VERSION 5.4 ;
NAMESCASESENSITIVE ON ;
BUSBITCHARS "[]" ;
DIVIDERCHAR "/" ;
UNITS
  DATABASE MICRONS 2000 ;
END UNITS
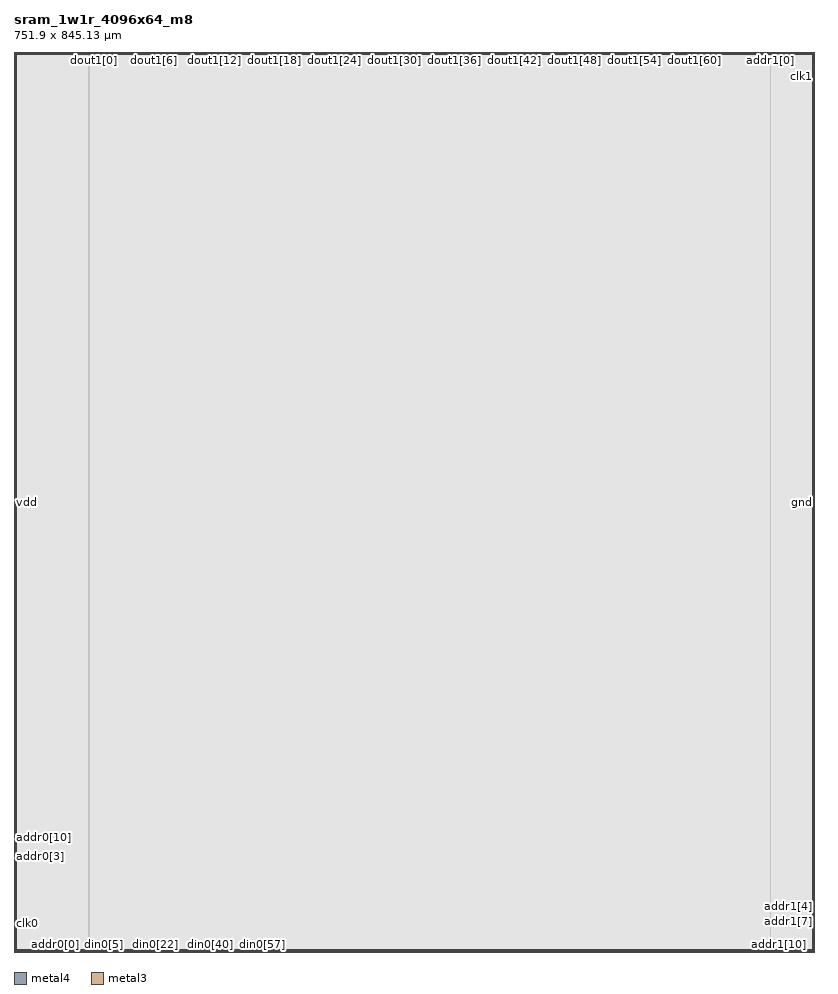
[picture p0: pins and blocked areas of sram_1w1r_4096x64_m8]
MACRO sram_1w1r_4096x64_m8
   CLASS BLOCK ;
   SIZE 751.9 BY 845.13 ;
   SYMMETRY X Y R90 ;
   PIN din0[0]
      DIRECTION INPUT ;
      PORT
         LAYER metal4 ;
         RECT  70.13 0.0 70.27 0.14 ;
      END
   END din0[0]
   PIN din0[1]
      DIRECTION INPUT ;
      PORT
         LAYER metal4 ;
         RECT  72.99 0.0 73.13 0.14 ;
      END
   END din0[1]
   PIN din0[2]
      DIRECTION INPUT ;
      PORT
         LAYER metal4 ;
         RECT  75.85 0.0 75.99 0.14 ;
      END
   END din0[2]
   PIN din0[3]
      DIRECTION INPUT ;
      PORT
         LAYER metal4 ;
         RECT  78.71 0.0 78.85 0.14 ;
      END
   END din0[3]
   PIN din0[4]
      DIRECTION INPUT ;
      PORT
         LAYER metal4 ;
         RECT  81.57 0.0 81.71 0.14 ;
      END
   END din0[4]
   PIN din0[5]
      DIRECTION INPUT ;
      PORT
         LAYER metal4 ;
         RECT  84.43 0.0 84.57 0.14 ;
      END
   END din0[5]
   PIN din0[6]
      DIRECTION INPUT ;
      PORT
         LAYER metal4 ;
         RECT  87.29 0.0 87.43 0.14 ;
      END
   END din0[6]
   PIN din0[7]
      DIRECTION INPUT ;
      PORT
         LAYER metal4 ;
         RECT  90.15 0.0 90.29 0.14 ;
      END
   END din0[7]
   PIN din0[8]
      DIRECTION INPUT ;
      PORT
         LAYER metal4 ;
         RECT  93.01 0.0 93.15 0.14 ;
      END
   END din0[8]
   PIN din0[9]
      DIRECTION INPUT ;
      PORT
         LAYER metal4 ;
         RECT  95.87 0.0 96.01 0.14 ;
      END
   END din0[9]
   PIN din0[10]
      DIRECTION INPUT ;
      PORT
         LAYER metal4 ;
         RECT  98.73 0.0 98.87 0.14 ;
      END
   END din0[10]
   PIN din0[11]
      DIRECTION INPUT ;
      PORT
         LAYER metal4 ;
         RECT  101.59 0.0 101.73 0.14 ;
      END
   END din0[11]
   PIN din0[12]
      DIRECTION INPUT ;
      PORT
         LAYER metal4 ;
         RECT  104.45 0.0 104.59 0.14 ;
      END
   END din0[12]
   PIN din0[13]
      DIRECTION INPUT ;
      PORT
         LAYER metal4 ;
         RECT  107.31 0.0 107.45 0.14 ;
      END
   END din0[13]
   PIN din0[14]
      DIRECTION INPUT ;
      PORT
         LAYER metal4 ;
         RECT  110.17 0.0 110.31 0.14 ;
      END
   END din0[14]
   PIN din0[15]
      DIRECTION INPUT ;
      PORT
         LAYER metal4 ;
         RECT  113.03 0.0 113.17 0.14 ;
      END
   END din0[15]
   PIN din0[16]
      DIRECTION INPUT ;
      PORT
         LAYER metal4 ;
         RECT  115.89 0.0 116.03 0.14 ;
      END
   END din0[16]
   PIN din0[17]
      DIRECTION INPUT ;
      PORT
         LAYER metal4 ;
         RECT  118.75 0.0 118.89 0.14 ;
      END
   END din0[17]
   PIN din0[18]
      DIRECTION INPUT ;
      PORT
         LAYER metal4 ;
         RECT  121.61 0.0 121.75 0.14 ;
      END
   END din0[18]
   PIN din0[19]
      DIRECTION INPUT ;
      PORT
         LAYER metal4 ;
         RECT  124.47 0.0 124.61 0.14 ;
      END
   END din0[19]
   PIN din0[20]
      DIRECTION INPUT ;
      PORT
         LAYER metal4 ;
         RECT  127.33 0.0 127.47 0.14 ;
      END
   END din0[20]
   PIN din0[21]
      DIRECTION INPUT ;
      PORT
         LAYER metal4 ;
         RECT  130.19 0.0 130.33 0.14 ;
      END
   END din0[21]
   PIN din0[22]
      DIRECTION INPUT ;
      PORT
         LAYER metal4 ;
         RECT  133.05 0.0 133.19 0.14 ;
      END
   END din0[22]
   PIN din0[23]
      DIRECTION INPUT ;
      PORT
         LAYER metal4 ;
         RECT  135.91 0.0 136.05 0.14 ;
      END
   END din0[23]
   PIN din0[24]
      DIRECTION INPUT ;
      PORT
         LAYER metal4 ;
         RECT  138.77 0.0 138.91 0.14 ;
      END
   END din0[24]
   PIN din0[25]
      DIRECTION INPUT ;
      PORT
         LAYER metal4 ;
         RECT  141.63 0.0 141.77 0.14 ;
      END
   END din0[25]
   PIN din0[26]
      DIRECTION INPUT ;
      PORT
         LAYER metal4 ;
         RECT  144.49 0.0 144.63 0.14 ;
      END
   END din0[26]
   PIN din0[27]
      DIRECTION INPUT ;
      PORT
         LAYER metal4 ;
         RECT  147.35 0.0 147.49 0.14 ;
      END
   END din0[27]
   PIN din0[28]
      DIRECTION INPUT ;
      PORT
         LAYER metal4 ;
         RECT  150.21 0.0 150.35 0.14 ;
      END
   END din0[28]
   PIN din0[29]
      DIRECTION INPUT ;
      PORT
         LAYER metal4 ;
         RECT  153.07 0.0 153.21 0.14 ;
      END
   END din0[29]
   PIN din0[30]
      DIRECTION INPUT ;
      PORT
         LAYER metal4 ;
         RECT  155.93 0.0 156.07 0.14 ;
      END
   END din0[30]
   PIN din0[31]
      DIRECTION INPUT ;
      PORT
         LAYER metal4 ;
         RECT  158.79 0.0 158.93 0.14 ;
      END
   END din0[31]
   PIN din0[32]
      DIRECTION INPUT ;
      PORT
         LAYER metal4 ;
         RECT  161.65 0.0 161.79 0.14 ;
      END
   END din0[32]
   PIN din0[33]
      DIRECTION INPUT ;
      PORT
         LAYER metal4 ;
         RECT  164.51 0.0 164.65 0.14 ;
      END
   END din0[33]
   PIN din0[34]
      DIRECTION INPUT ;
      PORT
         LAYER metal4 ;
         RECT  167.37 0.0 167.51 0.14 ;
      END
   END din0[34]
   PIN din0[35]
      DIRECTION INPUT ;
      PORT
         LAYER metal4 ;
         RECT  170.23 0.0 170.37 0.14 ;
      END
   END din0[35]
   PIN din0[36]
      DIRECTION INPUT ;
      PORT
         LAYER metal4 ;
         RECT  173.09 0.0 173.23 0.14 ;
      END
   END din0[36]
   PIN din0[37]
      DIRECTION INPUT ;
      PORT
         LAYER metal4 ;
         RECT  175.95 0.0 176.09 0.14 ;
      END
   END din0[37]
   PIN din0[38]
      DIRECTION INPUT ;
      PORT
         LAYER metal4 ;
         RECT  178.81 0.0 178.95 0.14 ;
      END
   END din0[38]
   PIN din0[39]
      DIRECTION INPUT ;
      PORT
         LAYER metal4 ;
         RECT  181.67 0.0 181.81 0.14 ;
      END
   END din0[39]
   PIN din0[40]
      DIRECTION INPUT ;
      PORT
         LAYER metal4 ;
         RECT  184.53 0.0 184.67 0.14 ;
      END
   END din0[40]
   PIN din0[41]
      DIRECTION INPUT ;
      PORT
         LAYER metal4 ;
         RECT  187.39 0.0 187.53 0.14 ;
      END
   END din0[41]
   PIN din0[42]
      DIRECTION INPUT ;
      PORT
         LAYER metal4 ;
         RECT  190.25 0.0 190.39 0.14 ;
      END
   END din0[42]
   PIN din0[43]
      DIRECTION INPUT ;
      PORT
         LAYER metal4 ;
         RECT  193.11 0.0 193.25 0.14 ;
      END
   END din0[43]
   PIN din0[44]
      DIRECTION INPUT ;
      PORT
         LAYER metal4 ;
         RECT  195.97 0.0 196.11 0.14 ;
      END
   END din0[44]
   PIN din0[45]
      DIRECTION INPUT ;
      PORT
         LAYER metal4 ;
         RECT  198.83 0.0 198.97 0.14 ;
      END
   END din0[45]
   PIN din0[46]
      DIRECTION INPUT ;
      PORT
         LAYER metal4 ;
         RECT  201.69 0.0 201.83 0.14 ;
      END
   END din0[46]
   PIN din0[47]
      DIRECTION INPUT ;
      PORT
         LAYER metal4 ;
         RECT  204.55 0.0 204.69 0.14 ;
      END
   END din0[47]
   PIN din0[48]
      DIRECTION INPUT ;
      PORT
         LAYER metal4 ;
         RECT  207.41 0.0 207.55 0.14 ;
      END
   END din0[48]
   PIN din0[49]
      DIRECTION INPUT ;
      PORT
         LAYER metal4 ;
         RECT  210.27 0.0 210.41 0.14 ;
      END
   END din0[49]
   PIN din0[50]
      DIRECTION INPUT ;
      PORT
         LAYER metal4 ;
         RECT  213.13 0.0 213.27 0.14 ;
      END
   END din0[50]
   PIN din0[51]
      DIRECTION INPUT ;
      PORT
         LAYER metal4 ;
         RECT  215.99 0.0 216.13 0.14 ;
      END
   END din0[51]
   PIN din0[52]
      DIRECTION INPUT ;
      PORT
         LAYER metal4 ;
         RECT  218.85 0.0 218.99 0.14 ;
      END
   END din0[52]
   PIN din0[53]
      DIRECTION INPUT ;
      PORT
         LAYER metal4 ;
         RECT  221.71 0.0 221.85 0.14 ;
      END
   END din0[53]
   PIN din0[54]
      DIRECTION INPUT ;
      PORT
         LAYER metal4 ;
         RECT  224.57 0.0 224.71 0.14 ;
      END
   END din0[54]
   PIN din0[55]
      DIRECTION INPUT ;
      PORT
         LAYER metal4 ;
         RECT  227.43 0.0 227.57 0.14 ;
      END
   END din0[55]
   PIN din0[56]
      DIRECTION INPUT ;
      PORT
         LAYER metal4 ;
         RECT  230.29 0.0 230.43 0.14 ;
      END
   END din0[56]
   PIN din0[57]
      DIRECTION INPUT ;
      PORT
         LAYER metal4 ;
         RECT  233.15 0.0 233.29 0.14 ;
      END
   END din0[57]
   PIN din0[58]
      DIRECTION INPUT ;
      PORT
         LAYER metal4 ;
         RECT  236.01 0.0 236.15 0.14 ;
      END
   END din0[58]
   PIN din0[59]
      DIRECTION INPUT ;
      PORT
         LAYER metal4 ;
         RECT  238.87 0.0 239.01 0.14 ;
      END
   END din0[59]
   PIN din0[60]
      DIRECTION INPUT ;
      PORT
         LAYER metal4 ;
         RECT  241.73 0.0 241.87 0.14 ;
      END
   END din0[60]
   PIN din0[61]
      DIRECTION INPUT ;
      PORT
         LAYER metal4 ;
         RECT  244.59 0.0 244.73 0.14 ;
      END
   END din0[61]
   PIN din0[62]
      DIRECTION INPUT ;
      PORT
         LAYER metal4 ;
         RECT  247.45 0.0 247.59 0.14 ;
      END
   END din0[62]
   PIN din0[63]
      DIRECTION INPUT ;
      PORT
         LAYER metal4 ;
         RECT  250.31 0.0 250.45 0.14 ;
      END
   END din0[63]
   PIN addr0[0]
      DIRECTION INPUT ;
      PORT
         LAYER metal4 ;
         RECT  38.67 0.0 38.81 0.14 ;
      END
   END addr0[0]
   PIN addr0[1]
      DIRECTION INPUT ;
      PORT
         LAYER metal4 ;
         RECT  41.53 0.0 41.67 0.14 ;
      END
   END addr0[1]
   PIN addr0[2]
      DIRECTION INPUT ;
      PORT
         LAYER metal4 ;
         RECT  44.39 0.0 44.53 0.14 ;
      END
   END addr0[2]
   PIN addr0[3]
      DIRECTION INPUT ;
      PORT
         LAYER metal3 ;
         RECT  0.0 89.64 0.14 89.78 ;
      END
   END addr0[3]
   PIN addr0[4]
      DIRECTION INPUT ;
      PORT
         LAYER metal3 ;
         RECT  0.0 92.37 0.14 92.51 ;
      END
   END addr0[4]
   PIN addr0[5]
      DIRECTION INPUT ;
      PORT
         LAYER metal3 ;
         RECT  0.0 94.58 0.14 94.72 ;
      END
   END addr0[5]
   PIN addr0[6]
      DIRECTION INPUT ;
      PORT
         LAYER metal3 ;
         RECT  0.0 97.31 0.14 97.45 ;
      END
   END addr0[6]
   PIN addr0[7]
      DIRECTION INPUT ;
      PORT
         LAYER metal3 ;
         RECT  0.0 99.52 0.14 99.66 ;
      END
   END addr0[7]
   PIN addr0[8]
      DIRECTION INPUT ;
      PORT
         LAYER metal3 ;
         RECT  0.0 102.25 0.14 102.39 ;
      END
   END addr0[8]
   PIN addr0[9]
      DIRECTION INPUT ;
      PORT
         LAYER metal3 ;
         RECT  0.0 104.46 0.14 104.6 ;
      END
   END addr0[9]
   PIN addr0[10]
      DIRECTION INPUT ;
      PORT
         LAYER metal3 ;
         RECT  0.0 107.19 0.14 107.33 ;
      END
   END addr0[10]
   PIN addr0[11]
      DIRECTION INPUT ;
      PORT
         LAYER metal3 ;
         RECT  0.0 109.4 0.14 109.54 ;
      END
   END addr0[11]
   PIN addr1[0]
      DIRECTION INPUT ;
      PORT
         LAYER metal4 ;
         RECT  710.23 844.99 710.37 845.13 ;
      END
   END addr1[0]
   PIN addr1[1]
      DIRECTION INPUT ;
      PORT
         LAYER metal4 ;
         RECT  707.37 844.99 707.51 845.13 ;
      END
   END addr1[1]
   PIN addr1[2]
      DIRECTION INPUT ;
      PORT
         LAYER metal4 ;
         RECT  704.51 844.99 704.65 845.13 ;
      END
   END addr1[2]
   PIN addr1[3]
      DIRECTION INPUT ;
      PORT
         LAYER metal3 ;
         RECT  751.76 45.57 751.9 45.71 ;
      END
   END addr1[3]
   PIN addr1[4]
      DIRECTION INPUT ;
      PORT
         LAYER metal3 ;
         RECT  751.76 42.84 751.9 42.98 ;
      END
   END addr1[4]
   PIN addr1[5]
      DIRECTION INPUT ;
      PORT
         LAYER metal3 ;
         RECT  751.76 40.63 751.9 40.77 ;
      END
   END addr1[5]
   PIN addr1[6]
      DIRECTION INPUT ;
      PORT
         LAYER metal3 ;
         RECT  751.76 37.9 751.9 38.04 ;
      END
   END addr1[6]
   PIN addr1[7]
      DIRECTION INPUT ;
      PORT
         LAYER metal3 ;
         RECT  751.76 35.69 751.9 35.83 ;
      END
   END addr1[7]
   PIN addr1[8]
      DIRECTION INPUT ;
      PORT
         LAYER metal3 ;
         RECT  751.76 32.96 751.9 33.1 ;
      END
   END addr1[8]
   PIN addr1[9]
      DIRECTION INPUT ;
      PORT
         LAYER metal4 ;
         RECT  719.375 0.0 719.52 0.14 ;
      END
   END addr1[9]
   PIN addr1[10]
      DIRECTION INPUT ;
      PORT
         LAYER metal4 ;
         RECT  718.52 0.0 718.665 0.14 ;
      END
   END addr1[10]
   PIN addr1[11]
      DIRECTION INPUT ;
      PORT
         LAYER metal4 ;
         RECT  718.805 0.0 718.95 0.14 ;
      END
   END addr1[11]
   PIN csb0
      DIRECTION INPUT ;
      PORT
         LAYER metal3 ;
         RECT  0.0 26.8 0.14 26.94 ;
      END
   END csb0
   PIN csb1
      DIRECTION INPUT ;
      PORT
         LAYER metal3 ;
         RECT  751.76 829.52 751.9 829.66 ;
      END
   END csb1
   PIN clk0
      DIRECTION INPUT ;
      PORT
         LAYER metal3 ;
         RECT  0.0 27.035 0.14 27.175 ;
      END
   END clk0
   PIN clk1
      DIRECTION INPUT ;
      PORT
         LAYER metal3 ;
         RECT  751.76 829.285 751.9 829.425 ;
      END
   END clk1
   PIN wmask0[0]
      DIRECTION INPUT ;
      PORT
         LAYER metal4 ;
         RECT  47.25 0.0 47.39 0.14 ;
      END
   END wmask0[0]
   PIN wmask0[1]
      DIRECTION INPUT ;
      PORT
         LAYER metal4 ;
         RECT  50.11 0.0 50.25 0.14 ;
      END
   END wmask0[1]
   PIN wmask0[2]
      DIRECTION INPUT ;
      PORT
         LAYER metal4 ;
         RECT  52.97 0.0 53.11 0.14 ;
      END
   END wmask0[2]
   PIN wmask0[3]
      DIRECTION INPUT ;
      PORT
         LAYER metal4 ;
         RECT  55.83 0.0 55.97 0.14 ;
      END
   END wmask0[3]
   PIN wmask0[4]
      DIRECTION INPUT ;
      PORT
         LAYER metal4 ;
         RECT  58.69 0.0 58.83 0.14 ;
      END
   END wmask0[4]
   PIN wmask0[5]
      DIRECTION INPUT ;
      PORT
         LAYER metal4 ;
         RECT  61.55 0.0 61.69 0.14 ;
      END
   END wmask0[5]
   PIN wmask0[6]
      DIRECTION INPUT ;
      PORT
         LAYER metal4 ;
         RECT  64.41 0.0 64.55 0.14 ;
      END
   END wmask0[6]
   PIN wmask0[7]
      DIRECTION INPUT ;
      PORT
         LAYER metal4 ;
         RECT  67.27 0.0 67.41 0.14 ;
      END
   END wmask0[7]
   PIN dout1[0]
      DIRECTION OUTPUT ;
      PORT
         LAYER metal4 ;
         RECT  75.01 844.99 75.15 845.13 ;
      END
   END dout1[0]
   PIN dout1[1]
      DIRECTION OUTPUT ;
      PORT
         LAYER metal4 ;
         RECT  84.41 844.99 84.55 845.13 ;
      END
   END dout1[1]
   PIN dout1[2]
      DIRECTION OUTPUT ;
      PORT
         LAYER metal4 ;
         RECT  93.81 844.99 93.95 845.13 ;
      END
   END dout1[2]
   PIN dout1[3]
      DIRECTION OUTPUT ;
      PORT
         LAYER metal4 ;
         RECT  103.21 844.99 103.35 845.13 ;
      END
   END dout1[3]
   PIN dout1[4]
      DIRECTION OUTPUT ;
      PORT
         LAYER metal4 ;
         RECT  112.61 844.99 112.75 845.13 ;
      END
   END dout1[4]
   PIN dout1[5]
      DIRECTION OUTPUT ;
      PORT
         LAYER metal4 ;
         RECT  122.01 844.99 122.15 845.13 ;
      END
   END dout1[5]
   PIN dout1[6]
      DIRECTION OUTPUT ;
      PORT
         LAYER metal4 ;
         RECT  131.41 844.99 131.55 845.13 ;
      END
   END dout1[6]
   PIN dout1[7]
      DIRECTION OUTPUT ;
      PORT
         LAYER metal4 ;
         RECT  140.81 844.99 140.95 845.13 ;
      END
   END dout1[7]
   PIN dout1[8]
      DIRECTION OUTPUT ;
      PORT
         LAYER metal4 ;
         RECT  150.21 844.99 150.35 845.13 ;
      END
   END dout1[8]
   PIN dout1[9]
      DIRECTION OUTPUT ;
      PORT
         LAYER metal4 ;
         RECT  159.61 844.99 159.75 845.13 ;
      END
   END dout1[9]
   PIN dout1[10]
      DIRECTION OUTPUT ;
      PORT
         LAYER metal4 ;
         RECT  169.01 844.99 169.15 845.13 ;
      END
   END dout1[10]
   PIN dout1[11]
      DIRECTION OUTPUT ;
      PORT
         LAYER metal4 ;
         RECT  178.41 844.99 178.55 845.13 ;
      END
   END dout1[11]
   PIN dout1[12]
      DIRECTION OUTPUT ;
      PORT
         LAYER metal4 ;
         RECT  187.81 844.99 187.95 845.13 ;
      END
   END dout1[12]
   PIN dout1[13]
      DIRECTION OUTPUT ;
      PORT
         LAYER metal4 ;
         RECT  197.21 844.99 197.35 845.13 ;
      END
   END dout1[13]
   PIN dout1[14]
      DIRECTION OUTPUT ;
      PORT
         LAYER metal4 ;
         RECT  206.61 844.99 206.75 845.13 ;
      END
   END dout1[14]
   PIN dout1[15]
      DIRECTION OUTPUT ;
      PORT
         LAYER metal4 ;
         RECT  216.01 844.99 216.15 845.13 ;
      END
   END dout1[15]
   PIN dout1[16]
      DIRECTION OUTPUT ;
      PORT
         LAYER metal4 ;
         RECT  225.41 844.99 225.55 845.13 ;
      END
   END dout1[16]
   PIN dout1[17]
      DIRECTION OUTPUT ;
      PORT
         LAYER metal4 ;
         RECT  234.81 844.99 234.95 845.13 ;
      END
   END dout1[17]
   PIN dout1[18]
      DIRECTION OUTPUT ;
      PORT
         LAYER metal4 ;
         RECT  244.21 844.99 244.35 845.13 ;
      END
   END dout1[18]
   PIN dout1[19]
      DIRECTION OUTPUT ;
      PORT
         LAYER metal4 ;
         RECT  253.61 844.99 253.75 845.13 ;
      END
   END dout1[19]
   PIN dout1[20]
      DIRECTION OUTPUT ;
      PORT
         LAYER metal4 ;
         RECT  263.01 844.99 263.15 845.13 ;
      END
   END dout1[20]
   PIN dout1[21]
      DIRECTION OUTPUT ;
      PORT
         LAYER metal4 ;
         RECT  272.41 844.99 272.55 845.13 ;
      END
   END dout1[21]
   PIN dout1[22]
      DIRECTION OUTPUT ;
      PORT
         LAYER metal4 ;
         RECT  281.81 844.99 281.95 845.13 ;
      END
   END dout1[22]
   PIN dout1[23]
      DIRECTION OUTPUT ;
      PORT
         LAYER metal4 ;
         RECT  291.21 844.99 291.35 845.13 ;
      END
   END dout1[23]
   PIN dout1[24]
      DIRECTION OUTPUT ;
      PORT
         LAYER metal4 ;
         RECT  300.61 844.99 300.75 845.13 ;
      END
   END dout1[24]
   PIN dout1[25]
      DIRECTION OUTPUT ;
      PORT
         LAYER metal4 ;
         RECT  310.01 844.99 310.15 845.13 ;
      END
   END dout1[25]
   PIN dout1[26]
      DIRECTION OUTPUT ;
      PORT
         LAYER metal4 ;
         RECT  319.41 844.99 319.55 845.13 ;
      END
   END dout1[26]
   PIN dout1[27]
      DIRECTION OUTPUT ;
      PORT
         LAYER metal4 ;
         RECT  328.81 844.99 328.95 845.13 ;
      END
   END dout1[27]
   PIN dout1[28]
      DIRECTION OUTPUT ;
      PORT
         LAYER metal4 ;
         RECT  338.21 844.99 338.35 845.13 ;
      END
   END dout1[28]
   PIN dout1[29]
      DIRECTION OUTPUT ;
      PORT
         LAYER metal4 ;
         RECT  347.61 844.99 347.75 845.13 ;
      END
   END dout1[29]
   PIN dout1[30]
      DIRECTION OUTPUT ;
      PORT
         LAYER metal4 ;
         RECT  357.01 844.99 357.15 845.13 ;
      END
   END dout1[30]
   PIN dout1[31]
      DIRECTION OUTPUT ;
      PORT
         LAYER metal4 ;
         RECT  366.41 844.99 366.55 845.13 ;
      END
   END dout1[31]
   PIN dout1[32]
      DIRECTION OUTPUT ;
      PORT
         LAYER metal4 ;
         RECT  375.81 844.99 375.95 845.13 ;
      END
   END dout1[32]
   PIN dout1[33]
      DIRECTION OUTPUT ;
      PORT
         LAYER metal4 ;
         RECT  385.21 844.99 385.35 845.13 ;
      END
   END dout1[33]
   PIN dout1[34]
      DIRECTION OUTPUT ;
      PORT
         LAYER metal4 ;
         RECT  394.61 844.99 394.75 845.13 ;
      END
   END dout1[34]
   PIN dout1[35]
      DIRECTION OUTPUT ;
      PORT
         LAYER metal4 ;
         RECT  404.01 844.99 404.15 845.13 ;
      END
   END dout1[35]
   PIN dout1[36]
      DIRECTION OUTPUT ;
      PORT
         LAYER metal4 ;
         RECT  413.41 844.99 413.55 845.13 ;
      END
   END dout1[36]
   PIN dout1[37]
      DIRECTION OUTPUT ;
      PORT
         LAYER metal4 ;
         RECT  422.81 844.99 422.95 845.13 ;
      END
   END dout1[37]
   PIN dout1[38]
      DIRECTION OUTPUT ;
      PORT
         LAYER metal4 ;
         RECT  432.21 844.99 432.35 845.13 ;
      END
   END dout1[38]
   PIN dout1[39]
      DIRECTION OUTPUT ;
      PORT
         LAYER metal4 ;
         RECT  441.61 844.99 441.75 845.13 ;
      END
   END dout1[39]
   PIN dout1[40]
      DIRECTION OUTPUT ;
      PORT
         LAYER metal4 ;
         RECT  451.01 844.99 451.15 845.13 ;
      END
   END dout1[40]
   PIN dout1[41]
      DIRECTION OUTPUT ;
      PORT
         LAYER metal4 ;
         RECT  460.41 844.99 460.55 845.13 ;
      END
   END dout1[41]
   PIN dout1[42]
      DIRECTION OUTPUT ;
      PORT
         LAYER metal4 ;
         RECT  469.81 844.99 469.95 845.13 ;
      END
   END dout1[42]
   PIN dout1[43]
      DIRECTION OUTPUT ;
      PORT
         LAYER metal4 ;
         RECT  479.21 844.99 479.35 845.13 ;
      END
   END dout1[43]
   PIN dout1[44]
      DIRECTION OUTPUT ;
      PORT
         LAYER metal4 ;
         RECT  488.61 844.99 488.75 845.13 ;
      END
   END dout1[44]
   PIN dout1[45]
      DIRECTION OUTPUT ;
      PORT
         LAYER metal4 ;
         RECT  498.01 844.99 498.15 845.13 ;
      END
   END dout1[45]
   PIN dout1[46]
      DIRECTION OUTPUT ;
      PORT
         LAYER metal4 ;
         RECT  507.41 844.99 507.55 845.13 ;
      END
   END dout1[46]
   PIN dout1[47]
      DIRECTION OUTPUT ;
      PORT
         LAYER metal4 ;
         RECT  516.81 844.99 516.95 845.13 ;
      END
   END dout1[47]
   PIN dout1[48]
      DIRECTION OUTPUT ;
      PORT
         LAYER metal4 ;
         RECT  526.21 844.99 526.35 845.13 ;
      END
   END dout1[48]
   PIN dout1[49]
      DIRECTION OUTPUT ;
      PORT
         LAYER metal4 ;
         RECT  535.61 844.99 535.75 845.13 ;
      END
   END dout1[49]
   PIN dout1[50]
      DIRECTION OUTPUT ;
      PORT
         LAYER metal4 ;
         RECT  545.01 844.99 545.15 845.13 ;
      END
   END dout1[50]
   PIN dout1[51]
      DIRECTION OUTPUT ;
      PORT
         LAYER metal4 ;
         RECT  554.41 844.99 554.55 845.13 ;
      END
   END dout1[51]
   PIN dout1[52]
      DIRECTION OUTPUT ;
      PORT
         LAYER metal4 ;
         RECT  563.81 844.99 563.95 845.13 ;
      END
   END dout1[52]
   PIN dout1[53]
      DIRECTION OUTPUT ;
      PORT
         LAYER metal4 ;
         RECT  573.21 844.99 573.35 845.13 ;
      END
   END dout1[53]
   PIN dout1[54]
      DIRECTION OUTPUT ;
      PORT
         LAYER metal4 ;
         RECT  582.61 844.99 582.75 845.13 ;
      END
   END dout1[54]
   PIN dout1[55]
      DIRECTION OUTPUT ;
      PORT
         LAYER metal4 ;
         RECT  592.01 844.99 592.15 845.13 ;
      END
   END dout1[55]
   PIN dout1[56]
      DIRECTION OUTPUT ;
      PORT
         LAYER metal4 ;
         RECT  601.41 844.99 601.55 845.13 ;
      END
   END dout1[56]
   PIN dout1[57]
      DIRECTION OUTPUT ;
      PORT
         LAYER metal4 ;
         RECT  610.81 844.99 610.95 845.13 ;
      END
   END dout1[57]
   PIN dout1[58]
      DIRECTION OUTPUT ;
      PORT
         LAYER metal4 ;
         RECT  620.21 844.99 620.35 845.13 ;
      END
   END dout1[58]
   PIN dout1[59]
      DIRECTION OUTPUT ;
      PORT
         LAYER metal4 ;
         RECT  629.61 844.99 629.75 845.13 ;
      END
   END dout1[59]
   PIN dout1[60]
      DIRECTION OUTPUT ;
      PORT
         LAYER metal4 ;
         RECT  639.01 844.99 639.15 845.13 ;
      END
   END dout1[60]
   PIN dout1[61]
      DIRECTION OUTPUT ;
      PORT
         LAYER metal4 ;
         RECT  648.41 844.99 648.55 845.13 ;
      END
   END dout1[61]
   PIN dout1[62]
      DIRECTION OUTPUT ;
      PORT
         LAYER metal4 ;
         RECT  657.81 844.99 657.95 845.13 ;
      END
   END dout1[62]
   PIN dout1[63]
      DIRECTION OUTPUT ;
      PORT
         LAYER metal4 ;
         RECT  667.21 844.99 667.35 845.13 ;
      END
   END dout1[63]
   PIN vdd
      DIRECTION INOUT ;
      USE POWER ; 
      SHAPE ABUTMENT ; 
      PORT
         LAYER metal4 ;
         RECT  0.0 0.0 0.7 845.13 ;
         LAYER metal4 ;
         RECT  751.2 0.0 751.9 845.13 ;
         LAYER metal3 ;
         RECT  0.0 0.0 751.9 0.7 ;
         LAYER metal3 ;
         RECT  0.0 844.43 751.9 845.13 ;
      END
   END vdd
   PIN gnd
      DIRECTION INOUT ;
      USE GROUND ; 
      SHAPE ABUTMENT ; 
      PORT
         LAYER metal4 ;
         RECT  1.4 1.4 2.1 843.73 ;
         LAYER metal3 ;
         RECT  1.4 1.4 750.5 2.1 ;
         LAYER metal4 ;
         RECT  749.8 1.4 750.5 843.73 ;
         LAYER metal3 ;
         RECT  1.4 843.03 750.5 843.73 ;
      END
   END gnd
   OBS
   LAYER  metal1 ;
      RECT  0.14 0.14 751.76 844.99 ;
   LAYER  metal2 ;
      RECT  0.14 0.14 751.76 844.99 ;
   LAYER  metal3 ;
      RECT  0.28 89.5 751.76 89.92 ;
      RECT  0.14 89.92 0.28 92.23 ;
      RECT  0.14 92.65 0.28 94.44 ;
      RECT  0.14 94.86 0.28 97.17 ;
      RECT  0.14 97.59 0.28 99.38 ;
      RECT  0.14 99.8 0.28 102.11 ;
      RECT  0.14 102.53 0.28 104.32 ;
      RECT  0.14 104.74 0.28 107.05 ;
      RECT  0.14 107.47 0.28 109.26 ;
      RECT  0.28 45.43 751.62 45.85 ;
      RECT  0.28 45.85 751.62 89.5 ;
      RECT  751.62 45.85 751.76 89.5 ;
      RECT  751.62 43.12 751.76 45.43 ;
      RECT  751.62 40.91 751.76 42.7 ;
      RECT  751.62 38.18 751.76 40.49 ;
      RECT  751.62 35.97 751.76 37.76 ;
      RECT  751.62 33.24 751.76 35.55 ;
      RECT  0.28 89.92 751.62 829.38 ;
      RECT  0.28 829.38 751.62 829.8 ;
      RECT  0.14 27.315 0.28 89.5 ;
      RECT  751.62 89.92 751.76 829.145 ;
      RECT  751.62 0.84 751.76 32.82 ;
      RECT  0.14 0.84 0.28 26.66 ;
      RECT  0.14 109.68 0.28 844.29 ;
      RECT  751.62 829.8 751.76 844.29 ;
      RECT  0.28 0.84 1.26 1.26 ;
      RECT  0.28 1.26 1.26 2.24 ;
      RECT  0.28 2.24 1.26 45.43 ;
      RECT  1.26 0.84 750.64 1.26 ;
      RECT  1.26 2.24 750.64 45.43 ;
      RECT  750.64 0.84 751.62 1.26 ;
      RECT  750.64 1.26 751.62 2.24 ;
      RECT  750.64 2.24 751.62 45.43 ;
      RECT  0.28 829.8 1.26 842.89 ;
      RECT  0.28 842.89 1.26 843.87 ;
      RECT  0.28 843.87 1.26 844.29 ;
      RECT  1.26 829.8 750.64 842.89 ;
      RECT  1.26 843.87 750.64 844.29 ;
      RECT  750.64 829.8 751.62 842.89 ;
      RECT  750.64 842.89 751.62 843.87 ;
      RECT  750.64 843.87 751.62 844.29 ;
   LAYER  metal4 ;
      RECT  69.85 0.42 70.55 844.99 ;
      RECT  70.55 0.14 72.71 0.42 ;
      RECT  73.41 0.14 75.57 0.42 ;
      RECT  76.27 0.14 78.43 0.42 ;
      RECT  79.13 0.14 81.29 0.42 ;
      RECT  81.99 0.14 84.15 0.42 ;
      RECT  84.85 0.14 87.01 0.42 ;
      RECT  87.71 0.14 89.87 0.42 ;
      RECT  90.57 0.14 92.73 0.42 ;
      RECT  93.43 0.14 95.59 0.42 ;
      RECT  96.29 0.14 98.45 0.42 ;
      RECT  99.15 0.14 101.31 0.42 ;
      RECT  102.01 0.14 104.17 0.42 ;
      RECT  104.87 0.14 107.03 0.42 ;
      RECT  107.73 0.14 109.89 0.42 ;
      RECT  110.59 0.14 112.75 0.42 ;
      RECT  113.45 0.14 115.61 0.42 ;
      RECT  116.31 0.14 118.47 0.42 ;
      RECT  119.17 0.14 121.33 0.42 ;
      RECT  122.03 0.14 124.19 0.42 ;
      RECT  124.89 0.14 127.05 0.42 ;
      RECT  127.75 0.14 129.91 0.42 ;
      RECT  130.61 0.14 132.77 0.42 ;
      RECT  133.47 0.14 135.63 0.42 ;
      RECT  136.33 0.14 138.49 0.42 ;
      RECT  139.19 0.14 141.35 0.42 ;
      RECT  142.05 0.14 144.21 0.42 ;
      RECT  144.91 0.14 147.07 0.42 ;
      RECT  147.77 0.14 149.93 0.42 ;
      RECT  150.63 0.14 152.79 0.42 ;
      RECT  153.49 0.14 155.65 0.42 ;
      RECT  156.35 0.14 158.51 0.42 ;
      RECT  159.21 0.14 161.37 0.42 ;
      RECT  162.07 0.14 164.23 0.42 ;
      RECT  164.93 0.14 167.09 0.42 ;
      RECT  167.79 0.14 169.95 0.42 ;
      RECT  170.65 0.14 172.81 0.42 ;
      RECT  173.51 0.14 175.67 0.42 ;
      RECT  176.37 0.14 178.53 0.42 ;
      RECT  179.23 0.14 181.39 0.42 ;
      RECT  182.09 0.14 184.25 0.42 ;
      RECT  184.95 0.14 187.11 0.42 ;
      RECT  187.81 0.14 189.97 0.42 ;
      RECT  190.67 0.14 192.83 0.42 ;
      RECT  193.53 0.14 195.69 0.42 ;
      RECT  196.39 0.14 198.55 0.42 ;
      RECT  199.25 0.14 201.41 0.42 ;
      RECT  202.11 0.14 204.27 0.42 ;
      RECT  204.97 0.14 207.13 0.42 ;
      RECT  207.83 0.14 209.99 0.42 ;
      RECT  210.69 0.14 212.85 0.42 ;
      RECT  213.55 0.14 215.71 0.42 ;
      RECT  216.41 0.14 218.57 0.42 ;
      RECT  219.27 0.14 221.43 0.42 ;
      RECT  222.13 0.14 224.29 0.42 ;
      RECT  224.99 0.14 227.15 0.42 ;
      RECT  227.85 0.14 230.01 0.42 ;
      RECT  230.71 0.14 232.87 0.42 ;
      RECT  233.57 0.14 235.73 0.42 ;
      RECT  236.43 0.14 238.59 0.42 ;
      RECT  239.29 0.14 241.45 0.42 ;
      RECT  242.15 0.14 244.31 0.42 ;
      RECT  245.01 0.14 247.17 0.42 ;
      RECT  247.87 0.14 250.03 0.42 ;
      RECT  39.09 0.14 41.25 0.42 ;
      RECT  41.95 0.14 44.11 0.42 ;
      RECT  70.55 0.42 709.95 844.71 ;
      RECT  709.95 0.42 710.65 844.71 ;
      RECT  707.79 844.71 709.95 844.99 ;
      RECT  704.93 844.71 707.09 844.99 ;
      RECT  250.73 0.14 718.245 0.42 ;
      RECT  44.81 0.14 46.97 0.42 ;
      RECT  47.67 0.14 49.83 0.42 ;
      RECT  50.53 0.14 52.69 0.42 ;
      RECT  53.39 0.14 55.55 0.42 ;
      RECT  56.25 0.14 58.41 0.42 ;
      RECT  59.11 0.14 61.27 0.42 ;
      RECT  61.97 0.14 64.13 0.42 ;
      RECT  64.83 0.14 66.99 0.42 ;
      RECT  67.69 0.14 69.85 0.42 ;
      RECT  70.55 844.71 74.73 844.99 ;
      RECT  75.43 844.71 84.13 844.99 ;
      RECT  84.83 844.71 93.53 844.99 ;
      RECT  94.23 844.71 102.93 844.99 ;
      RECT  103.63 844.71 112.33 844.99 ;
      RECT  113.03 844.71 121.73 844.99 ;
      RECT  122.43 844.71 131.13 844.99 ;
      RECT  131.83 844.71 140.53 844.99 ;
      RECT  141.23 844.71 149.93 844.99 ;
      RECT  150.63 844.71 159.33 844.99 ;
      RECT  160.03 844.71 168.73 844.99 ;
      RECT  169.43 844.71 178.13 844.99 ;
      RECT  178.83 844.71 187.53 844.99 ;
      RECT  188.23 844.71 196.93 844.99 ;
      RECT  197.63 844.71 206.33 844.99 ;
      RECT  207.03 844.71 215.73 844.99 ;
      RECT  216.43 844.71 225.13 844.99 ;
      RECT  225.83 844.71 234.53 844.99 ;
      RECT  235.23 844.71 243.93 844.99 ;
      RECT  244.63 844.71 253.33 844.99 ;
      RECT  254.03 844.71 262.73 844.99 ;
      RECT  263.43 844.71 272.13 844.99 ;
      RECT  272.83 844.71 281.53 844.99 ;
      RECT  282.23 844.71 290.93 844.99 ;
      RECT  291.63 844.71 300.33 844.99 ;
      RECT  301.03 844.71 309.73 844.99 ;
      RECT  310.43 844.71 319.13 844.99 ;
      RECT  319.83 844.71 328.53 844.99 ;
      RECT  329.23 844.71 337.93 844.99 ;
      RECT  338.63 844.71 347.33 844.99 ;
      RECT  348.03 844.71 356.73 844.99 ;
      RECT  357.43 844.71 366.13 844.99 ;
      RECT  366.83 844.71 375.53 844.99 ;
      RECT  376.23 844.71 384.93 844.99 ;
      RECT  385.63 844.71 394.33 844.99 ;
      RECT  395.03 844.71 403.73 844.99 ;
      RECT  404.43 844.71 413.13 844.99 ;
      RECT  413.83 844.71 422.53 844.99 ;
      RECT  423.23 844.71 431.93 844.99 ;
      RECT  432.63 844.71 441.33 844.99 ;
      RECT  442.03 844.71 450.73 844.99 ;
      RECT  451.43 844.71 460.13 844.99 ;
      RECT  460.83 844.71 469.53 844.99 ;
      RECT  470.23 844.71 478.93 844.99 ;
      RECT  479.63 844.71 488.33 844.99 ;
      RECT  489.03 844.71 497.73 844.99 ;
      RECT  498.43 844.71 507.13 844.99 ;
      RECT  507.83 844.71 516.53 844.99 ;
      RECT  517.23 844.71 525.93 844.99 ;
      RECT  526.63 844.71 535.33 844.99 ;
      RECT  536.03 844.71 544.73 844.99 ;
      RECT  545.43 844.71 554.13 844.99 ;
      RECT  554.83 844.71 563.53 844.99 ;
      RECT  564.23 844.71 572.93 844.99 ;
      RECT  573.63 844.71 582.33 844.99 ;
      RECT  583.03 844.71 591.73 844.99 ;
      RECT  592.43 844.71 601.13 844.99 ;
      RECT  601.83 844.71 610.53 844.99 ;
      RECT  611.23 844.71 619.93 844.99 ;
      RECT  620.63 844.71 629.33 844.99 ;
      RECT  630.03 844.71 638.73 844.99 ;
      RECT  639.43 844.71 648.13 844.99 ;
      RECT  648.83 844.71 657.53 844.99 ;
      RECT  658.23 844.71 666.93 844.99 ;
      RECT  667.63 844.71 704.23 844.99 ;
      RECT  0.98 0.14 38.39 0.42 ;
      RECT  710.65 844.71 750.92 844.99 ;
      RECT  719.795 0.14 750.92 0.42 ;
      RECT  0.98 0.42 1.12 1.12 ;
      RECT  0.98 1.12 1.12 844.01 ;
      RECT  0.98 844.01 1.12 844.99 ;
      RECT  1.12 0.42 2.38 1.12 ;
      RECT  1.12 844.01 2.38 844.99 ;
      RECT  2.38 0.42 69.85 1.12 ;
      RECT  2.38 1.12 69.85 844.01 ;
      RECT  2.38 844.01 69.85 844.99 ;
      RECT  710.65 0.42 749.52 1.12 ;
      RECT  710.65 1.12 749.52 844.01 ;
      RECT  710.65 844.01 749.52 844.71 ;
      RECT  749.52 0.42 750.78 1.12 ;
      RECT  749.52 844.01 750.78 844.71 ;
      RECT  750.78 0.42 750.92 1.12 ;
      RECT  750.78 1.12 750.92 844.01 ;
      RECT  750.78 844.01 750.92 844.71 ;
   END
END    sram_1w1r_4096x64_m8
END    LIBRARY
